VERSION 5.7 ;
  NOWIREEXTENSIONATPIN ON ;
  DIVIDERCHAR "/" ;
  BUSBITCHARS "[]" ;
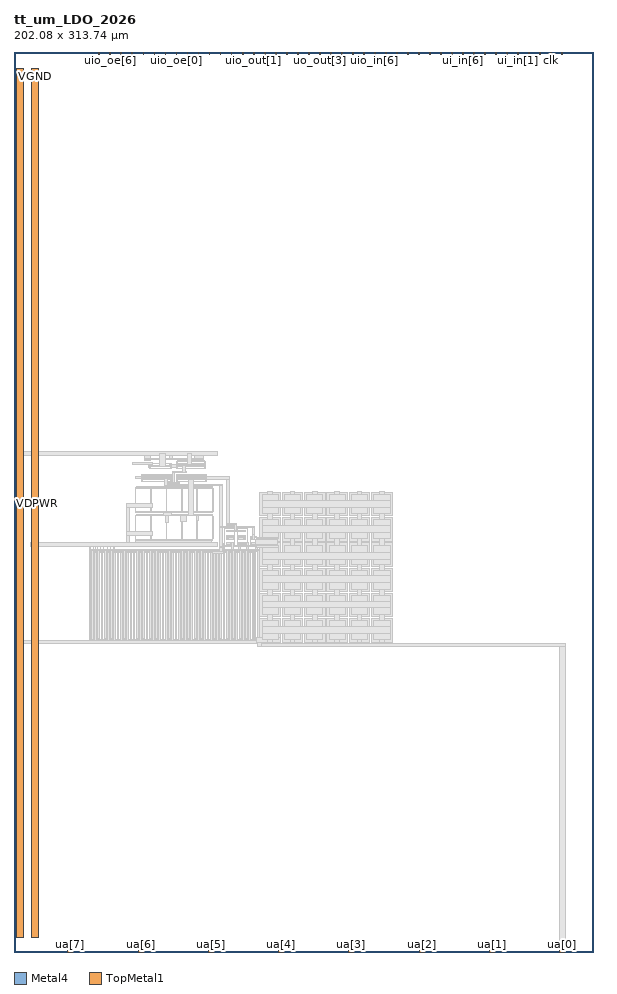
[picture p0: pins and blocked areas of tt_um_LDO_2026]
MACRO tt_um_LDO_2026
  CLASS BLOCK ;
  FOREIGN tt_um_LDO_2026 ;
  ORIGIN 0.000 0.000 ;
  SIZE 202.080 BY 313.740 ;
  PIN clk
    PORT
      LAYER Metal4 ;
        RECT 187.050 312.740 187.350 313.740 ;
    END
  END clk
  PIN ena
    PORT
      LAYER Metal4 ;
        RECT 190.890 312.740 191.190 313.740 ;
    END
  END ena
  PIN rst_n
    PORT
      LAYER Metal4 ;
        RECT 183.210 312.740 183.510 313.740 ;
    END
  END rst_n
  PIN ua[0]
    ANTENNADIFFAREA 559.200012 ;
    PORT
      LAYER TopMetal1 ;
        RECT 190.165 0.000 191.915 2.000 ;
    END
  END ua[0]
  PIN ua[1]
    PORT
      LAYER TopMetal1 ;
        RECT 165.685 0.000 167.435 2.000 ;
    END
  END ua[1]
  PIN ua[2]
    PORT
      LAYER TopMetal1 ;
        RECT 141.205 0.000 142.955 2.000 ;
    END
  END ua[2]
  PIN ua[3]
    PORT
      LAYER TopMetal1 ;
        RECT 116.725 0.000 118.475 2.000 ;
    END
  END ua[3]
  PIN ua[4]
    PORT
      LAYER TopMetal1 ;
        RECT 92.245 0.000 93.995 2.000 ;
    END
  END ua[4]
  PIN ua[5]
    PORT
      LAYER TopMetal1 ;
        RECT 67.765 0.000 69.515 2.000 ;
    END
  END ua[5]
  PIN ua[6]
    PORT
      LAYER TopMetal1 ;
        RECT 43.285 0.000 45.035 2.000 ;
    END
  END ua[6]
  PIN ua[7]
    PORT
      LAYER TopMetal1 ;
        RECT 18.805 0.000 20.555 2.000 ;
    END
  END ua[7]
  PIN ui_in[0]
    PORT
      LAYER Metal4 ;
        RECT 179.370 312.740 179.670 313.740 ;
    END
  END ui_in[0]
  PIN ui_in[1]
    PORT
      LAYER Metal4 ;
        RECT 175.530 312.740 175.830 313.740 ;
    END
  END ui_in[1]
  PIN ui_in[2]
    PORT
      LAYER Metal4 ;
        RECT 171.690 312.740 171.990 313.740 ;
    END
  END ui_in[2]
  PIN ui_in[3]
    PORT
      LAYER Metal4 ;
        RECT 167.850 312.740 168.150 313.740 ;
    END
  END ui_in[3]
  PIN ui_in[4]
    PORT
      LAYER Metal4 ;
        RECT 164.010 312.740 164.310 313.740 ;
    END
  END ui_in[4]
  PIN ui_in[5]
    PORT
      LAYER Metal4 ;
        RECT 160.170 312.740 160.470 313.740 ;
    END
  END ui_in[5]
  PIN ui_in[6]
    PORT
      LAYER Metal4 ;
        RECT 156.330 312.740 156.630 313.740 ;
    END
  END ui_in[6]
  PIN ui_in[7]
    PORT
      LAYER Metal4 ;
        RECT 152.490 312.740 152.790 313.740 ;
    END
  END ui_in[7]
  PIN uio_in[0]
    PORT
      LAYER Metal4 ;
        RECT 148.650 312.740 148.950 313.740 ;
    END
  END uio_in[0]
  PIN uio_in[1]
    PORT
      LAYER Metal4 ;
        RECT 144.810 312.740 145.110 313.740 ;
    END
  END uio_in[1]
  PIN uio_in[2]
    PORT
      LAYER Metal4 ;
        RECT 140.970 312.740 141.270 313.740 ;
    END
  END uio_in[2]
  PIN uio_in[3]
    PORT
      LAYER Metal4 ;
        RECT 137.130 312.740 137.430 313.740 ;
    END
  END uio_in[3]
  PIN uio_in[4]
    PORT
      LAYER Metal4 ;
        RECT 133.290 312.740 133.590 313.740 ;
    END
  END uio_in[4]
  PIN uio_in[5]
    PORT
      LAYER Metal4 ;
        RECT 129.450 312.740 129.750 313.740 ;
    END
  END uio_in[5]
  PIN uio_in[6]
    PORT
      LAYER Metal4 ;
        RECT 125.610 312.740 125.910 313.740 ;
    END
  END uio_in[6]
  PIN uio_in[7]
    PORT
      LAYER Metal4 ;
        RECT 121.770 312.740 122.070 313.740 ;
    END
  END uio_in[7]
  PIN uio_oe[0]
    PORT
      LAYER Metal4 ;
        RECT 56.490 312.740 56.790 313.740 ;
    END
  END uio_oe[0]
  PIN uio_oe[1]
    PORT
      LAYER Metal4 ;
        RECT 52.650 312.740 52.950 313.740 ;
    END
  END uio_oe[1]
  PIN uio_oe[2]
    PORT
      LAYER Metal4 ;
        RECT 48.810 312.740 49.110 313.740 ;
    END
  END uio_oe[2]
  PIN uio_oe[3]
    PORT
      LAYER Metal4 ;
        RECT 44.970 312.740 45.270 313.740 ;
    END
  END uio_oe[3]
  PIN uio_oe[4]
    PORT
      LAYER Metal4 ;
        RECT 41.130 312.740 41.430 313.740 ;
    END
  END uio_oe[4]
  PIN uio_oe[5]
    PORT
      LAYER Metal4 ;
        RECT 37.290 312.740 37.590 313.740 ;
    END
  END uio_oe[5]
  PIN uio_oe[6]
    PORT
      LAYER Metal4 ;
        RECT 33.450 312.740 33.750 313.740 ;
    END
  END uio_oe[6]
  PIN uio_oe[7]
    PORT
      LAYER Metal4 ;
        RECT 29.610 312.740 29.910 313.740 ;
    END
  END uio_oe[7]
  PIN uio_out[0]
    PORT
      LAYER Metal4 ;
        RECT 87.210 312.740 87.510 313.740 ;
    END
  END uio_out[0]
  PIN uio_out[1]
    PORT
      LAYER Metal4 ;
        RECT 83.370 312.740 83.670 313.740 ;
    END
  END uio_out[1]
  PIN uio_out[2]
    PORT
      LAYER Metal4 ;
        RECT 79.530 312.740 79.830 313.740 ;
    END
  END uio_out[2]
  PIN uio_out[3]
    PORT
      LAYER Metal4 ;
        RECT 75.690 312.740 75.990 313.740 ;
    END
  END uio_out[3]
  PIN uio_out[4]
    PORT
      LAYER Metal4 ;
        RECT 71.850 312.740 72.150 313.740 ;
    END
  END uio_out[4]
  PIN uio_out[5]
    PORT
      LAYER Metal4 ;
        RECT 68.010 312.740 68.310 313.740 ;
    END
  END uio_out[5]
  PIN uio_out[6]
    PORT
      LAYER Metal4 ;
        RECT 64.170 312.740 64.470 313.740 ;
    END
  END uio_out[6]
  PIN uio_out[7]
    PORT
      LAYER Metal4 ;
        RECT 60.330 312.740 60.630 313.740 ;
    END
  END uio_out[7]
  PIN uo_out[0]
    PORT
      LAYER Metal4 ;
        RECT 117.930 312.740 118.230 313.740 ;
    END
  END uo_out[0]
  PIN uo_out[1]
    PORT
      LAYER Metal4 ;
        RECT 114.090 312.740 114.390 313.740 ;
    END
  END uo_out[1]
  PIN uo_out[2]
    PORT
      LAYER Metal4 ;
        RECT 110.250 312.740 110.550 313.740 ;
    END
  END uo_out[2]
  PIN uo_out[3]
    PORT
      LAYER Metal4 ;
        RECT 106.410 312.740 106.710 313.740 ;
    END
  END uo_out[3]
  PIN uo_out[4]
    PORT
      LAYER Metal4 ;
        RECT 102.570 312.740 102.870 313.740 ;
    END
  END uo_out[4]
  PIN uo_out[5]
    PORT
      LAYER Metal4 ;
        RECT 98.730 312.740 99.030 313.740 ;
    END
  END uo_out[5]
  PIN uo_out[6]
    PORT
      LAYER Metal4 ;
        RECT 94.890 312.740 95.190 313.740 ;
    END
  END uo_out[6]
  PIN uo_out[7]
    PORT
      LAYER Metal4 ;
        RECT 91.050 312.740 91.350 313.740 ;
    END
  END uo_out[7]
  PIN VDPWR
    ANTENNADIFFAREA 562.940613 ;
    PORT
      LAYER TopMetal1 ;
        RECT 1.000 5.000 3.400 308.000 ;
    END
  END VDPWR
  PIN VGND
    ANTENNADIFFAREA 90.833000 ;
    PORT
      LAYER TopMetal1 ;
        RECT 6.000 5.000 8.400 308.000 ;
    END
  END VGND
  OBS
      LAYER GatPoly ;
        RECT 56.500 170.430 56.870 170.910 ;
        RECT 66.540 170.430 66.910 170.910 ;
        RECT 47.060 169.630 47.430 170.110 ;
        RECT 54.680 169.630 55.050 170.110 ;
        RECT 56.500 169.570 56.870 170.050 ;
        RECT 66.540 169.570 66.910 170.050 ;
        RECT 47.060 168.770 47.430 169.250 ;
        RECT 54.680 168.770 55.050 169.250 ;
        RECT 56.500 168.710 56.870 169.190 ;
        RECT 66.540 168.710 66.910 169.190 ;
        RECT 44.290 165.770 44.660 166.170 ;
        RECT 54.660 165.770 55.030 166.170 ;
        RECT 56.500 165.730 56.870 166.130 ;
        RECT 66.870 165.730 67.240 166.130 ;
        RECT 44.290 164.990 44.660 165.390 ;
        RECT 54.660 164.990 55.030 165.390 ;
        RECT 56.500 164.950 56.870 165.350 ;
        RECT 66.870 164.950 67.240 165.350 ;
        RECT 44.290 164.210 44.660 164.610 ;
        RECT 54.660 164.210 55.030 164.610 ;
        RECT 56.500 164.170 56.870 164.570 ;
        RECT 66.870 164.170 67.240 164.570 ;
        RECT 42.570 161.740 47.570 162.110 ;
        RECT 47.950 161.740 52.950 162.110 ;
        RECT 53.330 161.740 58.330 162.110 ;
        RECT 58.710 161.740 63.710 162.110 ;
        RECT 64.090 161.740 69.090 162.110 ;
        RECT 42.570 153.270 47.570 153.640 ;
        RECT 47.950 153.270 52.950 153.640 ;
        RECT 53.330 153.270 58.330 153.640 ;
        RECT 58.710 153.270 63.710 153.640 ;
        RECT 64.090 153.270 69.090 153.640 ;
        RECT 42.570 152.020 47.570 152.390 ;
        RECT 47.950 152.020 52.950 152.390 ;
        RECT 53.330 152.020 58.330 152.390 ;
        RECT 58.710 152.020 63.710 152.390 ;
        RECT 64.090 152.020 69.090 152.390 ;
        RECT 73.930 146.595 74.430 147.025 ;
        RECT 74.910 146.595 75.410 147.025 ;
        RECT 75.890 146.595 76.390 147.025 ;
        RECT 78.390 146.575 78.890 147.005 ;
        RECT 79.370 146.575 79.870 147.005 ;
        RECT 80.350 146.575 80.850 147.005 ;
        RECT 73.930 144.865 74.430 145.295 ;
        RECT 74.910 144.865 75.410 145.295 ;
        RECT 75.890 144.865 76.390 145.295 ;
        RECT 78.390 144.845 78.890 145.275 ;
        RECT 79.370 144.845 79.870 145.275 ;
        RECT 80.350 144.845 80.850 145.275 ;
        RECT 42.570 143.550 47.570 143.920 ;
        RECT 47.950 143.550 52.950 143.920 ;
        RECT 53.330 143.550 58.330 143.920 ;
        RECT 58.710 143.550 63.710 143.920 ;
        RECT 64.090 143.550 69.090 143.920 ;
        RECT 73.930 143.915 74.430 144.345 ;
        RECT 74.910 143.915 75.410 144.345 ;
        RECT 75.890 143.915 76.390 144.345 ;
        RECT 78.390 143.895 78.890 144.325 ;
        RECT 79.370 143.895 79.870 144.325 ;
        RECT 80.350 143.895 80.850 144.325 ;
        RECT 82.930 143.625 83.930 144.055 ;
        RECT 73.930 142.185 74.430 142.615 ;
        RECT 74.910 142.185 75.410 142.615 ;
        RECT 75.890 142.185 76.390 142.615 ;
        RECT 78.390 142.165 78.890 142.595 ;
        RECT 79.370 142.165 79.870 142.595 ;
        RECT 80.350 142.165 80.850 142.595 ;
        RECT 82.930 142.195 83.930 142.625 ;
        RECT 27.670 139.095 28.070 139.465 ;
        RECT 28.790 139.095 29.190 139.465 ;
        RECT 29.910 139.095 30.310 139.465 ;
        RECT 31.030 139.095 31.430 139.465 ;
        RECT 32.150 139.095 32.550 139.465 ;
        RECT 33.270 139.095 33.670 139.465 ;
        RECT 34.390 139.095 34.790 139.465 ;
        RECT 35.510 139.095 35.910 139.465 ;
        RECT 36.630 139.095 37.030 139.465 ;
        RECT 37.750 139.095 38.150 139.465 ;
        RECT 38.870 139.095 39.270 139.465 ;
        RECT 39.990 139.095 40.390 139.465 ;
        RECT 41.110 139.095 41.510 139.465 ;
        RECT 42.230 139.095 42.630 139.465 ;
        RECT 43.350 139.095 43.750 139.465 ;
        RECT 44.470 139.095 44.870 139.465 ;
        RECT 45.590 139.095 45.990 139.465 ;
        RECT 46.710 139.095 47.110 139.465 ;
        RECT 47.830 139.095 48.230 139.465 ;
        RECT 48.950 139.095 49.350 139.465 ;
        RECT 50.070 139.095 50.470 139.465 ;
        RECT 51.190 139.095 51.590 139.465 ;
        RECT 52.310 139.095 52.710 139.465 ;
        RECT 53.430 139.095 53.830 139.465 ;
        RECT 54.550 139.095 54.950 139.465 ;
        RECT 55.670 139.095 56.070 139.465 ;
        RECT 56.790 139.095 57.190 139.465 ;
        RECT 57.910 139.095 58.310 139.465 ;
        RECT 59.030 139.095 59.430 139.465 ;
        RECT 60.150 139.095 60.550 139.465 ;
        RECT 61.270 139.095 61.670 139.465 ;
        RECT 62.390 139.095 62.790 139.465 ;
        RECT 63.510 139.095 63.910 139.465 ;
        RECT 64.630 139.095 65.030 139.465 ;
        RECT 65.750 139.095 66.150 139.465 ;
        RECT 66.870 139.095 67.270 139.465 ;
        RECT 67.990 139.095 68.390 139.465 ;
        RECT 69.110 139.095 69.510 139.465 ;
        RECT 70.230 139.095 70.630 139.465 ;
        RECT 71.350 139.095 71.750 139.465 ;
        RECT 72.470 139.095 72.870 139.465 ;
        RECT 73.590 139.095 73.990 139.465 ;
        RECT 74.710 139.095 75.110 139.465 ;
        RECT 75.830 139.095 76.230 139.465 ;
        RECT 76.950 139.095 77.350 139.465 ;
        RECT 78.070 139.095 78.470 139.465 ;
        RECT 79.190 139.095 79.590 139.465 ;
        RECT 80.310 139.095 80.710 139.465 ;
        RECT 81.430 139.095 81.830 139.465 ;
        RECT 82.550 139.095 82.950 139.465 ;
        RECT 27.670 108.725 28.070 109.095 ;
        RECT 28.790 108.725 29.190 109.095 ;
        RECT 29.910 108.725 30.310 109.095 ;
        RECT 31.030 108.725 31.430 109.095 ;
        RECT 32.150 108.725 32.550 109.095 ;
        RECT 33.270 108.725 33.670 109.095 ;
        RECT 34.390 108.725 34.790 109.095 ;
        RECT 35.510 108.725 35.910 109.095 ;
        RECT 36.630 108.725 37.030 109.095 ;
        RECT 37.750 108.725 38.150 109.095 ;
        RECT 38.870 108.725 39.270 109.095 ;
        RECT 39.990 108.725 40.390 109.095 ;
        RECT 41.110 108.725 41.510 109.095 ;
        RECT 42.230 108.725 42.630 109.095 ;
        RECT 43.350 108.725 43.750 109.095 ;
        RECT 44.470 108.725 44.870 109.095 ;
        RECT 45.590 108.725 45.990 109.095 ;
        RECT 46.710 108.725 47.110 109.095 ;
        RECT 47.830 108.725 48.230 109.095 ;
        RECT 48.950 108.725 49.350 109.095 ;
        RECT 50.070 108.725 50.470 109.095 ;
        RECT 51.190 108.725 51.590 109.095 ;
        RECT 52.310 108.725 52.710 109.095 ;
        RECT 53.430 108.725 53.830 109.095 ;
        RECT 54.550 108.725 54.950 109.095 ;
        RECT 55.670 108.725 56.070 109.095 ;
        RECT 56.790 108.725 57.190 109.095 ;
        RECT 57.910 108.725 58.310 109.095 ;
        RECT 59.030 108.725 59.430 109.095 ;
        RECT 60.150 108.725 60.550 109.095 ;
        RECT 61.270 108.725 61.670 109.095 ;
        RECT 62.390 108.725 62.790 109.095 ;
        RECT 63.510 108.725 63.910 109.095 ;
        RECT 64.630 108.725 65.030 109.095 ;
        RECT 65.750 108.725 66.150 109.095 ;
        RECT 66.870 108.725 67.270 109.095 ;
        RECT 67.990 108.725 68.390 109.095 ;
        RECT 69.110 108.725 69.510 109.095 ;
        RECT 70.230 108.725 70.630 109.095 ;
        RECT 71.350 108.725 71.750 109.095 ;
        RECT 72.470 108.725 72.870 109.095 ;
        RECT 73.590 108.725 73.990 109.095 ;
        RECT 74.710 108.725 75.110 109.095 ;
        RECT 75.830 108.725 76.230 109.095 ;
        RECT 76.950 108.725 77.350 109.095 ;
        RECT 78.070 108.725 78.470 109.095 ;
        RECT 79.190 108.725 79.590 109.095 ;
        RECT 80.310 108.725 80.710 109.095 ;
        RECT 81.430 108.725 81.830 109.095 ;
        RECT 82.550 108.725 82.950 109.095 ;
      LAYER Metal1 ;
        RECT 1.840 174.530 2.540 174.700 ;
        RECT 1.190 173.250 70.810 174.530 ;
        RECT 45.320 172.140 47.720 173.250 ;
        RECT 50.980 173.130 51.680 173.250 ;
        RECT 54.070 172.140 55.380 173.250 ;
        RECT 60.710 173.030 61.410 173.250 ;
        RECT 62.780 172.140 66.210 173.250 ;
        RECT 45.320 171.650 66.210 172.140 ;
        RECT 45.320 171.510 47.720 171.650 ;
        RECT 62.780 171.500 66.210 171.650 ;
        RECT 47.750 170.430 48.450 170.680 ;
        RECT 47.500 170.300 54.890 170.430 ;
        RECT 47.130 168.580 47.290 170.300 ;
        RECT 47.500 170.170 54.980 170.300 ;
        RECT 47.750 170.060 48.450 170.170 ;
        RECT 54.070 169.980 54.980 170.170 ;
        RECT 54.820 169.960 54.980 169.980 ;
        RECT 56.570 169.960 56.730 171.100 ;
        RECT 56.940 170.970 66.470 171.230 ;
        RECT 60.750 170.370 61.450 170.720 ;
        RECT 56.940 170.110 66.470 170.370 ;
        RECT 60.750 170.100 61.450 170.110 ;
        RECT 51.340 169.570 52.040 169.880 ;
        RECT 47.500 169.310 54.610 169.570 ;
        RECT 51.340 169.260 52.040 169.310 ;
        RECT 54.820 169.060 56.730 169.960 ;
        RECT 58.740 169.510 59.440 169.520 ;
        RECT 56.940 169.250 66.470 169.510 ;
        RECT 47.500 168.450 54.610 168.710 ;
        RECT 54.820 168.580 54.980 169.060 ;
        RECT 56.570 168.520 56.730 169.060 ;
        RECT 58.740 168.900 59.440 169.250 ;
        RECT 56.940 168.390 66.470 168.650 ;
        RECT 66.680 168.520 66.840 171.100 ;
        RECT 55.400 167.395 56.100 167.640 ;
        RECT 58.920 167.395 59.620 167.970 ;
        RECT 55.400 167.150 60.260 167.395 ;
        RECT 44.360 165.650 44.520 166.360 ;
        RECT 44.730 166.230 54.590 166.490 ;
        RECT 42.510 165.030 44.520 165.650 ;
        RECT 44.730 165.450 54.590 165.710 ;
        RECT 44.360 164.020 44.520 165.030 ;
        RECT 44.730 164.670 54.590 164.930 ;
        RECT 53.990 164.150 54.590 164.170 ;
        RECT 44.730 163.890 54.590 164.150 ;
        RECT 54.800 164.020 54.960 166.360 ;
        RECT 53.990 163.760 54.590 163.890 ;
        RECT 53.990 163.755 54.630 163.760 ;
        RECT 55.400 163.755 56.100 167.150 ;
        RECT 56.570 163.980 56.730 166.320 ;
        RECT 56.940 166.190 66.800 166.450 ;
        RECT 56.940 165.410 66.800 165.670 ;
        RECT 67.010 165.660 67.170 166.320 ;
        RECT 61.150 164.890 61.850 165.090 ;
        RECT 56.940 164.630 66.800 164.890 ;
        RECT 67.010 164.870 74.965 165.660 ;
        RECT 61.150 164.470 61.850 164.630 ;
        RECT 56.940 164.110 57.610 164.130 ;
        RECT 56.940 163.850 66.800 164.110 ;
        RECT 67.010 163.980 67.170 164.870 ;
        RECT 56.940 163.755 57.610 163.850 ;
        RECT 52.770 162.890 53.470 163.360 ;
        RECT 53.990 163.350 57.610 163.755 ;
        RECT 55.400 163.200 56.100 163.350 ;
        RECT 52.360 162.530 72.720 162.890 ;
        RECT 42.380 161.880 69.280 162.040 ;
        RECT 40.160 155.920 40.340 155.930 ;
        RECT 39.220 155.720 40.340 155.920 ;
        RECT 39.190 155.100 40.340 155.720 ;
        RECT 39.220 154.960 40.340 155.100 ;
        RECT 39.220 146.380 40.380 154.960 ;
        RECT 42.250 153.710 42.510 161.670 ;
        RECT 47.630 156.030 47.890 161.670 ;
        RECT 47.410 155.410 48.110 156.030 ;
        RECT 47.630 153.710 47.890 155.410 ;
        RECT 53.010 153.710 53.270 161.670 ;
        RECT 58.390 153.710 58.650 161.670 ;
        RECT 63.770 153.710 64.030 161.670 ;
        RECT 69.150 153.710 69.410 161.670 ;
        RECT 42.380 153.340 69.280 153.500 ;
        RECT 52.180 152.320 55.020 153.340 ;
        RECT 61.560 152.320 62.260 152.770 ;
        RECT 42.380 152.160 69.280 152.320 ;
        RECT 52.180 152.150 55.020 152.160 ;
        RECT 39.220 145.920 40.340 146.380 ;
        RECT 39.190 145.300 40.340 145.920 ;
        RECT 39.220 145.280 40.340 145.300 ;
        RECT 39.220 142.760 40.380 145.280 ;
        RECT 42.250 143.990 42.510 151.950 ;
        RECT 47.630 146.360 47.890 151.950 ;
        RECT 52.960 149.810 54.030 152.150 ;
        RECT 58.160 150.150 60.220 152.160 ;
        RECT 61.560 152.150 62.260 152.160 ;
        RECT 63.770 150.330 64.390 152.160 ;
        RECT 47.340 145.740 48.040 146.360 ;
        RECT 47.630 143.990 47.890 145.740 ;
        RECT 53.010 143.990 53.270 149.810 ;
        RECT 58.390 143.990 58.650 150.150 ;
        RECT 63.770 143.990 64.030 150.330 ;
        RECT 69.150 143.990 69.410 151.950 ;
        RECT 71.800 148.280 72.720 162.530 ;
        RECT 74.175 149.440 74.965 164.870 ;
        RECT 74.175 149.160 77.720 149.440 ;
        RECT 74.170 149.090 77.720 149.160 ;
        RECT 74.170 148.660 77.730 149.090 ;
        RECT 77.030 148.470 77.730 148.660 ;
        RECT 71.800 147.920 83.790 148.280 ;
        RECT 42.380 143.620 69.280 143.780 ;
        RECT 25.020 142.750 40.380 142.760 ;
        RECT 5.885 142.740 41.060 142.750 ;
        RECT 42.470 142.740 68.980 143.380 ;
        RECT 5.885 141.460 70.810 142.740 ;
        RECT 5.885 141.400 41.060 141.460 ;
        RECT 26.270 139.765 26.430 141.400 ;
        RECT 26.670 139.765 26.830 141.400 ;
        RECT 27.690 139.765 27.850 141.400 ;
        RECT 28.370 139.765 28.530 141.400 ;
        RECT 29.050 139.765 29.210 141.400 ;
        RECT 30.070 139.765 30.230 141.400 ;
        RECT 31.090 139.765 31.250 141.400 ;
        RECT 32.450 139.765 32.610 141.400 ;
        RECT 33.470 139.765 33.630 141.400 ;
        RECT 34.830 139.765 34.990 141.400 ;
        RECT 39.830 141.380 41.060 141.400 ;
        RECT 71.800 140.510 72.720 147.920 ;
        RECT 73.290 147.505 77.030 147.665 ;
        RECT 73.290 142.575 73.450 147.505 ;
        RECT 73.950 146.705 74.440 147.065 ;
        RECT 73.950 146.690 74.410 146.705 ;
        RECT 74.930 146.675 75.420 147.035 ;
        RECT 75.910 146.665 76.400 147.025 ;
        RECT 73.950 144.875 74.440 145.235 ;
        RECT 74.930 144.845 75.420 145.205 ;
        RECT 75.910 145.195 76.370 145.200 ;
        RECT 75.910 144.835 76.400 145.195 ;
        RECT 73.950 144.005 74.440 144.365 ;
        RECT 74.910 143.995 75.430 144.355 ;
        RECT 75.890 143.995 76.410 144.355 ;
        RECT 72.970 141.825 73.540 142.575 ;
        RECT 73.950 142.175 74.440 142.555 ;
        RECT 74.920 142.195 75.410 142.555 ;
        RECT 75.900 142.195 76.390 142.555 ;
        RECT 76.870 141.825 77.030 147.505 ;
        RECT 77.750 147.485 81.490 147.645 ;
        RECT 77.750 141.825 77.910 147.485 ;
        RECT 78.410 146.670 78.870 147.005 ;
        RECT 79.390 146.670 79.850 147.005 ;
        RECT 80.370 146.670 80.830 147.005 ;
        RECT 78.390 144.865 78.880 145.225 ;
        RECT 79.390 144.855 79.880 145.215 ;
        RECT 80.370 144.855 80.860 145.215 ;
        RECT 78.410 143.995 78.900 144.355 ;
        RECT 79.390 143.995 79.880 144.355 ;
        RECT 78.410 143.990 78.870 143.995 ;
        RECT 79.390 143.990 79.850 143.995 ;
        RECT 80.370 143.985 80.860 144.345 ;
        RECT 81.330 142.595 81.490 147.485 ;
        RECT 83.100 145.600 83.790 147.920 ;
        RECT 83.100 144.980 83.800 145.600 ;
        RECT 83.100 144.940 83.790 144.980 ;
        RECT 82.290 144.535 84.570 144.695 ;
        RECT 78.340 141.825 78.910 142.585 ;
        RECT 79.380 142.155 79.870 142.515 ;
        RECT 80.360 142.165 80.850 142.525 ;
        RECT 81.130 141.825 81.700 142.595 ;
        RECT 82.290 141.825 82.450 144.535 ;
        RECT 82.950 143.715 83.910 144.105 ;
        RECT 84.410 142.535 84.570 144.535 ;
        RECT 82.950 142.185 83.910 142.530 ;
        RECT 84.190 141.825 84.760 142.535 ;
        RECT 72.970 141.385 84.760 141.825 ;
        RECT 72.970 139.765 73.540 141.385 ;
        RECT 78.340 139.765 78.910 141.385 ;
        RECT 81.130 139.765 81.700 141.385 ;
        RECT 84.190 139.765 84.760 141.385 ;
        RECT 26.270 139.605 84.760 139.765 ;
        RECT 26.270 108.585 26.430 139.605 ;
        RECT 26.670 139.600 26.830 139.605 ;
        RECT 28.370 139.600 28.530 139.605 ;
        RECT 72.970 139.595 73.540 139.605 ;
        RECT 84.190 139.555 84.760 139.605 ;
        RECT 26.630 139.235 83.990 139.395 ;
        RECT 26.630 108.955 26.790 139.235 ;
        RECT 27.010 109.165 27.610 139.025 ;
        RECT 28.130 109.165 28.730 139.025 ;
        RECT 29.250 109.165 29.850 139.025 ;
        RECT 30.370 109.165 30.970 139.025 ;
        RECT 31.490 109.165 32.090 139.025 ;
        RECT 32.610 109.165 33.210 139.025 ;
        RECT 33.730 109.165 34.330 139.025 ;
        RECT 34.850 109.165 35.450 139.025 ;
        RECT 35.970 109.165 36.570 139.025 ;
        RECT 37.090 109.165 37.690 139.025 ;
        RECT 38.210 109.165 38.810 139.025 ;
        RECT 39.330 109.165 39.930 139.025 ;
        RECT 40.450 109.165 41.050 139.025 ;
        RECT 41.570 109.165 42.170 139.025 ;
        RECT 42.690 109.165 43.290 139.025 ;
        RECT 43.810 109.165 44.410 139.025 ;
        RECT 44.930 109.165 45.530 139.025 ;
        RECT 46.050 109.165 46.650 139.025 ;
        RECT 47.170 109.165 47.770 139.025 ;
        RECT 48.290 109.165 48.890 139.025 ;
        RECT 49.410 109.165 50.010 139.025 ;
        RECT 50.530 109.165 51.130 139.025 ;
        RECT 51.650 109.165 52.250 139.025 ;
        RECT 52.770 109.165 53.370 139.025 ;
        RECT 53.890 109.165 54.490 139.025 ;
        RECT 55.010 109.165 55.610 139.025 ;
        RECT 56.130 109.165 56.730 139.025 ;
        RECT 57.250 109.165 57.850 139.025 ;
        RECT 58.370 109.165 58.970 139.025 ;
        RECT 59.490 109.165 60.090 139.025 ;
        RECT 60.610 109.165 61.210 139.025 ;
        RECT 61.730 109.165 62.330 139.025 ;
        RECT 62.850 109.165 63.450 139.025 ;
        RECT 63.970 109.165 64.570 139.025 ;
        RECT 65.090 109.165 65.690 139.025 ;
        RECT 66.210 109.165 66.810 139.025 ;
        RECT 67.330 109.165 67.930 139.025 ;
        RECT 68.450 109.165 69.050 139.025 ;
        RECT 69.570 109.165 70.170 139.025 ;
        RECT 70.690 109.165 71.290 139.025 ;
        RECT 71.810 109.165 72.410 139.025 ;
        RECT 72.930 109.165 73.530 139.025 ;
        RECT 74.050 109.165 74.650 139.025 ;
        RECT 75.170 109.165 75.770 139.025 ;
        RECT 76.290 109.165 76.890 139.025 ;
        RECT 77.410 109.165 78.010 139.025 ;
        RECT 78.530 109.165 79.130 139.025 ;
        RECT 79.650 109.165 80.250 139.025 ;
        RECT 80.770 109.165 81.370 139.025 ;
        RECT 81.890 109.165 82.490 139.025 ;
        RECT 83.010 109.165 83.610 139.025 ;
        RECT 83.830 108.955 83.990 139.235 ;
        RECT 26.630 108.795 83.990 108.955 ;
        RECT 84.190 108.585 84.350 139.555 ;
        RECT 26.270 108.425 84.350 108.585 ;
        RECT 84.970 106.590 192.190 107.580 ;
        RECT 190.130 0.050 192.190 106.590 ;
      LAYER Metal2 ;
        RECT 1.885 174.040 2.495 174.740 ;
        RECT 51.025 173.750 51.635 173.790 ;
        RECT 47.795 170.590 48.405 170.720 ;
        RECT 41.200 169.930 48.450 170.590 ;
        RECT 50.670 169.270 52.770 173.750 ;
        RECT 60.500 170.000 61.860 173.920 ;
        RECT 58.785 169.490 59.395 169.560 ;
        RECT 51.385 169.220 51.995 169.270 ;
        RECT 58.630 167.150 59.700 169.490 ;
        RECT 52.610 162.640 53.440 164.980 ;
        RECT 61.195 164.580 61.805 165.130 ;
        RECT 39.190 156.280 40.820 156.310 ;
        RECT 39.190 155.060 48.250 156.280 ;
        RECT 40.340 154.960 48.250 155.060 ;
        RECT 60.860 152.100 62.570 164.580 ;
        RECT 77.075 149.085 77.685 149.130 ;
        RECT 73.930 146.615 75.390 147.045 ;
        RECT 75.960 146.995 76.320 147.020 ;
        RECT 77.000 146.995 77.730 149.085 ;
        RECT 78.460 146.995 78.820 147.000 ;
        RECT 75.950 146.685 78.840 146.995 ;
        RECT 75.960 146.650 76.320 146.685 ;
        RECT 78.460 146.630 78.820 146.685 ;
        RECT 40.340 146.540 48.250 146.600 ;
        RECT 79.330 146.595 80.790 147.025 ;
        RECT 39.190 145.280 48.250 146.540 ;
        RECT 83.145 145.385 83.755 145.640 ;
        RECT 39.190 145.260 40.510 145.280 ;
        RECT 74.000 145.225 74.360 145.240 ;
        RECT 73.950 143.965 74.370 145.225 ;
        RECT 74.930 144.845 76.390 145.275 ;
        RECT 78.430 144.845 79.890 145.275 ;
        RECT 74.930 143.935 76.390 144.365 ;
        RECT 78.420 143.935 79.880 144.365 ;
        RECT 80.390 144.005 80.810 145.265 ;
        RECT 80.420 143.950 80.780 144.005 ;
        RECT 83.000 143.680 83.860 145.385 ;
        RECT 84.860 143.105 85.500 144.525 ;
        RECT 84.860 142.705 88.230 143.105 ;
        RECT 7.035 141.850 7.645 142.550 ;
        RECT 73.970 142.175 75.430 142.605 ;
        RECT 71.965 140.690 72.575 141.390 ;
        RECT 75.820 140.455 76.400 142.615 ;
        RECT 78.390 142.165 78.860 142.565 ;
        RECT 79.390 142.145 80.850 142.575 ;
        RECT 82.840 142.075 88.230 142.705 ;
        RECT 82.840 142.065 85.500 142.075 ;
        RECT 26.710 139.945 85.565 140.455 ;
        RECT 27.010 109.065 27.640 139.945 ;
        RECT 28.090 108.470 28.720 139.395 ;
        RECT 29.250 109.155 29.880 139.945 ;
        RECT 30.350 108.470 30.980 139.395 ;
        RECT 31.490 109.155 32.120 139.945 ;
        RECT 32.570 108.470 33.200 139.395 ;
        RECT 33.730 109.155 34.360 139.945 ;
        RECT 34.820 108.470 35.450 139.385 ;
        RECT 35.970 109.135 36.600 139.945 ;
        RECT 37.070 108.470 37.700 139.385 ;
        RECT 38.210 109.145 38.840 139.945 ;
        RECT 39.300 108.470 39.930 139.365 ;
        RECT 40.470 109.155 41.100 139.945 ;
        RECT 41.540 108.470 42.170 139.405 ;
        RECT 42.700 109.155 43.330 139.945 ;
        RECT 43.770 108.470 44.400 139.395 ;
        RECT 44.930 109.155 45.560 139.945 ;
        RECT 46.020 108.470 46.650 139.355 ;
        RECT 47.170 109.155 47.800 139.945 ;
        RECT 48.290 108.470 48.920 139.375 ;
        RECT 49.420 109.165 50.050 139.945 ;
        RECT 50.520 108.470 51.150 139.375 ;
        RECT 51.630 109.155 52.260 139.945 ;
        RECT 52.750 108.470 53.380 139.355 ;
        RECT 53.890 109.175 54.520 139.945 ;
        RECT 54.980 108.470 55.610 139.375 ;
        RECT 56.130 109.135 56.760 139.945 ;
        RECT 57.260 108.470 57.890 139.375 ;
        RECT 58.370 109.145 59.000 139.945 ;
        RECT 59.470 108.470 60.100 139.385 ;
        RECT 60.620 109.145 61.250 139.945 ;
        RECT 61.680 108.470 62.310 139.365 ;
        RECT 62.870 109.135 63.500 139.945 ;
        RECT 63.940 108.470 64.570 139.395 ;
        RECT 65.110 109.145 65.740 139.945 ;
        RECT 66.160 108.470 66.790 139.375 ;
        RECT 67.310 109.135 67.940 139.945 ;
        RECT 68.430 108.470 69.060 139.325 ;
        RECT 69.570 109.145 70.200 139.945 ;
        RECT 70.680 108.470 71.310 139.355 ;
        RECT 71.790 109.145 72.420 139.945 ;
        RECT 72.920 108.470 73.550 139.395 ;
        RECT 74.070 109.135 74.700 139.945 ;
        RECT 75.140 108.470 75.770 139.425 ;
        RECT 76.270 109.145 76.900 139.945 ;
        RECT 77.380 108.470 78.010 139.395 ;
        RECT 78.530 109.135 79.160 139.945 ;
        RECT 79.630 108.470 80.260 139.405 ;
        RECT 80.760 109.145 81.390 139.945 ;
        RECT 81.890 108.470 82.520 139.355 ;
        RECT 83.010 109.155 83.640 139.945 ;
        RECT 84.975 109.755 85.485 139.945 ;
        RECT 2.070 108.455 25.030 108.470 ;
        RECT 26.290 108.455 84.390 108.470 ;
        RECT 2.070 107.640 84.390 108.455 ;
        RECT 84.690 108.005 86.170 109.755 ;
        RECT 84.970 106.590 86.170 108.005 ;
        RECT 190.785 1.860 191.395 2.560 ;
      LAYER Metal3 ;
        RECT 1.840 174.085 2.540 174.695 ;
        RECT 84.790 142.705 85.510 142.905 ;
        RECT 6.990 141.895 7.690 142.505 ;
        RECT 71.920 141.080 72.620 141.345 ;
        RECT 71.690 139.450 72.850 141.080 ;
        RECT 69.220 139.050 72.870 139.450 ;
        RECT 71.690 139.040 72.850 139.050 ;
        RECT 2.090 108.140 2.810 108.340 ;
        RECT 84.770 108.230 85.470 108.840 ;
        RECT 190.740 1.905 191.440 2.515 ;
      LAYER Metal4 ;
        RECT 1.885 174.040 2.495 174.740 ;
        RECT 7.035 141.850 7.645 142.550 ;
        RECT 85.050 142.445 85.250 143.165 ;
        RECT 2.350 107.880 2.550 108.600 ;
        RECT 84.815 108.185 85.425 108.885 ;
        RECT 190.785 1.860 191.395 2.560 ;
      LAYER Metal5 ;
        RECT 1.460 173.660 2.920 175.120 ;
        RECT 88.790 160.225 89.790 160.525 ;
        RECT 96.590 160.225 97.590 160.525 ;
        RECT 104.390 160.225 105.390 160.525 ;
        RECT 112.190 160.225 113.190 160.525 ;
        RECT 119.990 160.225 120.990 160.525 ;
        RECT 127.790 160.225 128.790 160.525 ;
        RECT 85.690 152.025 92.890 160.225 ;
        RECT 93.490 152.025 100.690 160.225 ;
        RECT 101.290 152.025 108.490 160.225 ;
        RECT 109.090 152.025 116.290 160.225 ;
        RECT 116.890 152.025 124.090 160.225 ;
        RECT 124.690 152.025 131.890 160.225 ;
        RECT 88.790 151.425 89.790 152.025 ;
        RECT 96.590 151.425 97.590 152.025 ;
        RECT 104.390 151.425 105.390 152.025 ;
        RECT 112.190 151.425 113.190 152.025 ;
        RECT 119.990 151.425 120.990 152.025 ;
        RECT 127.790 151.425 128.790 152.025 ;
        RECT 85.690 143.225 92.890 151.425 ;
        RECT 93.490 143.225 100.690 151.425 ;
        RECT 101.290 143.225 108.490 151.425 ;
        RECT 109.090 143.225 116.290 151.425 ;
        RECT 116.890 143.225 124.090 151.425 ;
        RECT 124.690 143.225 131.890 151.425 ;
        RECT 6.610 141.470 8.070 142.930 ;
        RECT 84.840 142.495 85.460 143.115 ;
        RECT 88.790 142.625 89.790 143.225 ;
        RECT 96.590 142.625 97.590 143.225 ;
        RECT 104.390 142.625 105.390 143.225 ;
        RECT 112.190 142.625 113.190 143.225 ;
        RECT 119.990 142.625 120.990 143.225 ;
        RECT 127.790 142.625 128.790 143.225 ;
        RECT 85.690 134.425 92.890 142.625 ;
        RECT 93.490 134.425 100.690 142.625 ;
        RECT 101.290 134.425 108.490 142.625 ;
        RECT 109.090 134.425 116.290 142.625 ;
        RECT 116.890 134.425 124.090 142.625 ;
        RECT 124.690 134.425 131.890 142.625 ;
        RECT 88.790 133.825 89.790 134.425 ;
        RECT 96.590 133.825 97.590 134.425 ;
        RECT 104.390 133.825 105.390 134.425 ;
        RECT 112.190 133.825 113.190 134.425 ;
        RECT 119.990 133.825 120.990 134.425 ;
        RECT 127.790 133.825 128.790 134.425 ;
        RECT 85.690 125.625 92.890 133.825 ;
        RECT 93.490 125.625 100.690 133.825 ;
        RECT 101.290 125.625 108.490 133.825 ;
        RECT 109.090 125.625 116.290 133.825 ;
        RECT 116.890 125.625 124.090 133.825 ;
        RECT 124.690 125.625 131.890 133.825 ;
        RECT 88.790 125.025 89.790 125.625 ;
        RECT 96.590 125.025 97.590 125.625 ;
        RECT 104.390 125.025 105.390 125.625 ;
        RECT 112.190 125.025 113.190 125.625 ;
        RECT 119.990 125.025 120.990 125.625 ;
        RECT 127.790 125.025 128.790 125.625 ;
        RECT 85.690 116.825 92.890 125.025 ;
        RECT 93.490 116.825 100.690 125.025 ;
        RECT 101.290 116.825 108.490 125.025 ;
        RECT 109.090 116.825 116.290 125.025 ;
        RECT 116.890 116.825 124.090 125.025 ;
        RECT 124.690 116.825 131.890 125.025 ;
        RECT 88.790 116.225 89.790 116.825 ;
        RECT 96.590 116.225 97.590 116.825 ;
        RECT 104.390 116.225 105.390 116.825 ;
        RECT 112.190 116.225 113.190 116.825 ;
        RECT 119.990 116.225 120.990 116.825 ;
        RECT 127.790 116.225 128.790 116.825 ;
        RECT 85.690 109.755 92.890 116.225 ;
        RECT 2.140 107.930 2.760 108.550 ;
        RECT 84.690 108.025 92.890 109.755 ;
        RECT 93.490 108.025 100.690 116.225 ;
        RECT 101.290 108.025 108.490 116.225 ;
        RECT 109.090 108.025 116.290 116.225 ;
        RECT 116.890 108.025 124.090 116.225 ;
        RECT 124.690 108.025 131.890 116.225 ;
        RECT 84.690 108.005 86.170 108.025 ;
        RECT 88.790 107.725 89.790 108.025 ;
        RECT 96.590 107.725 97.590 108.025 ;
        RECT 104.390 107.725 105.390 108.025 ;
        RECT 112.190 107.725 113.190 108.025 ;
        RECT 119.990 107.725 120.990 108.025 ;
        RECT 127.790 107.725 128.790 108.025 ;
        RECT 190.360 1.480 191.820 2.940 ;
      LAYER TopMetal1 ;
        RECT 88.470 159.425 90.110 160.525 ;
        RECT 96.270 159.425 97.910 160.525 ;
        RECT 104.070 159.425 105.710 160.525 ;
        RECT 111.870 159.425 113.510 160.525 ;
        RECT 119.670 159.425 121.310 160.525 ;
        RECT 127.470 159.425 129.110 160.525 ;
        RECT 86.490 157.355 92.090 159.425 ;
        RECT 94.290 157.355 99.890 159.425 ;
        RECT 102.090 157.355 107.690 159.425 ;
        RECT 109.890 157.355 115.490 159.425 ;
        RECT 117.690 157.355 123.290 159.425 ;
        RECT 125.490 157.355 131.090 159.425 ;
        RECT 86.490 155.075 131.090 157.355 ;
        RECT 86.490 152.825 92.090 155.075 ;
        RECT 94.290 152.825 99.890 155.075 ;
        RECT 102.090 152.825 107.690 155.075 ;
        RECT 109.890 152.825 115.490 155.075 ;
        RECT 117.690 152.825 123.290 155.075 ;
        RECT 125.490 152.825 131.090 155.075 ;
        RECT 88.470 150.625 90.110 152.825 ;
        RECT 96.270 150.625 97.910 152.825 ;
        RECT 104.070 150.625 105.710 152.825 ;
        RECT 111.870 150.625 113.510 152.825 ;
        RECT 119.670 150.625 121.310 152.825 ;
        RECT 127.470 150.625 129.110 152.825 ;
        RECT 86.490 148.505 92.090 150.625 ;
        RECT 94.290 148.505 99.890 150.625 ;
        RECT 102.090 148.505 107.690 150.625 ;
        RECT 109.890 148.505 115.490 150.625 ;
        RECT 117.690 148.505 123.290 150.625 ;
        RECT 125.490 148.505 131.090 150.625 ;
        RECT 86.490 146.225 131.090 148.505 ;
        RECT 86.490 144.525 92.090 146.225 ;
        RECT 84.655 144.025 92.090 144.525 ;
        RECT 94.290 144.025 99.890 146.225 ;
        RECT 102.090 144.025 107.690 146.225 ;
        RECT 109.890 144.025 115.490 146.225 ;
        RECT 117.690 144.025 123.290 146.225 ;
        RECT 125.490 144.025 131.090 146.225 ;
        RECT 84.655 143.625 91.960 144.025 ;
        RECT 84.330 141.985 91.960 143.625 ;
        RECT 84.655 141.825 91.960 141.985 ;
        RECT 96.270 141.825 97.910 144.025 ;
        RECT 104.070 141.825 105.710 144.025 ;
        RECT 111.870 141.825 113.510 144.025 ;
        RECT 119.670 141.825 121.310 144.025 ;
        RECT 127.470 141.825 129.110 144.025 ;
        RECT 84.655 140.915 92.090 141.825 ;
        RECT 86.490 139.265 92.090 140.915 ;
        RECT 94.290 139.265 99.890 141.825 ;
        RECT 102.090 139.265 107.690 141.825 ;
        RECT 109.890 139.265 115.490 141.825 ;
        RECT 117.690 139.265 123.290 141.825 ;
        RECT 125.490 139.265 131.090 141.825 ;
        RECT 86.490 136.985 131.300 139.265 ;
        RECT 86.490 135.225 92.090 136.985 ;
        RECT 94.290 135.225 99.890 136.985 ;
        RECT 102.090 135.225 107.690 136.985 ;
        RECT 109.890 135.225 115.490 136.985 ;
        RECT 117.690 135.225 123.290 136.985 ;
        RECT 125.490 135.225 131.090 136.985 ;
        RECT 88.470 133.025 90.110 135.225 ;
        RECT 96.270 133.025 97.910 135.225 ;
        RECT 104.070 133.025 105.710 135.225 ;
        RECT 111.870 133.025 113.510 135.225 ;
        RECT 119.670 133.025 121.310 135.225 ;
        RECT 127.470 133.025 129.110 135.225 ;
        RECT 86.490 131.095 92.090 133.025 ;
        RECT 94.290 131.095 99.890 133.025 ;
        RECT 102.090 131.095 107.690 133.025 ;
        RECT 109.890 131.095 115.490 133.025 ;
        RECT 117.690 131.095 123.290 133.025 ;
        RECT 125.490 131.095 131.090 133.025 ;
        RECT 86.490 128.815 131.090 131.095 ;
        RECT 86.490 126.425 92.090 128.815 ;
        RECT 94.290 126.425 99.890 128.815 ;
        RECT 102.090 126.425 107.690 128.815 ;
        RECT 109.890 126.425 115.490 128.815 ;
        RECT 117.690 126.425 123.290 128.815 ;
        RECT 125.490 126.425 131.090 128.815 ;
        RECT 88.470 124.225 90.110 126.425 ;
        RECT 96.270 124.225 97.910 126.425 ;
        RECT 104.070 124.225 105.710 126.425 ;
        RECT 111.870 124.225 113.510 126.425 ;
        RECT 119.670 124.225 121.310 126.425 ;
        RECT 127.470 124.225 129.110 126.425 ;
        RECT 86.490 122.315 92.090 124.225 ;
        RECT 94.290 122.315 99.890 124.225 ;
        RECT 102.090 122.315 107.690 124.225 ;
        RECT 109.890 122.315 115.490 124.225 ;
        RECT 117.690 122.315 123.290 124.225 ;
        RECT 125.490 122.315 131.090 124.225 ;
        RECT 86.490 120.035 131.090 122.315 ;
        RECT 86.490 117.625 92.090 120.035 ;
        RECT 94.290 117.625 99.890 120.035 ;
        RECT 102.090 117.625 107.690 120.035 ;
        RECT 109.890 117.625 115.490 120.035 ;
        RECT 117.690 117.625 123.290 120.035 ;
        RECT 125.490 117.625 131.090 120.035 ;
        RECT 88.470 115.425 90.110 117.625 ;
        RECT 96.270 115.425 97.910 117.625 ;
        RECT 104.070 115.425 105.710 117.625 ;
        RECT 111.870 115.425 113.510 117.625 ;
        RECT 119.670 115.425 121.310 117.625 ;
        RECT 127.470 115.425 129.110 117.625 ;
        RECT 86.490 113.305 92.090 115.425 ;
        RECT 94.290 113.305 99.890 115.425 ;
        RECT 102.090 113.305 107.690 115.425 ;
        RECT 109.890 113.305 115.490 115.425 ;
        RECT 117.690 113.305 123.290 115.425 ;
        RECT 125.490 113.305 131.090 115.425 ;
        RECT 86.490 111.025 131.090 113.305 ;
        RECT 86.490 108.825 92.090 111.025 ;
        RECT 94.290 108.825 99.890 111.025 ;
        RECT 102.090 108.825 107.690 111.025 ;
        RECT 109.890 108.825 115.490 111.025 ;
        RECT 117.690 108.825 123.290 111.025 ;
        RECT 125.490 108.825 131.090 111.025 ;
        RECT 88.470 107.725 90.110 108.825 ;
        RECT 96.270 107.725 97.910 108.825 ;
        RECT 104.070 107.725 105.710 108.825 ;
        RECT 111.870 107.725 113.510 108.825 ;
        RECT 119.670 107.725 121.310 108.825 ;
        RECT 127.470 107.725 129.110 108.825 ;
        RECT 190.040 2.000 192.140 3.260 ;
        RECT 190.040 1.160 190.165 2.000 ;
        RECT 191.915 1.160 192.140 2.000 ;
  END
END tt_um_LDO_2026
END LIBRARY

